One B-rep face of a CAD part: STEP entity #280.
In plain terms, the planar face has unit normal (1, 0, 0).
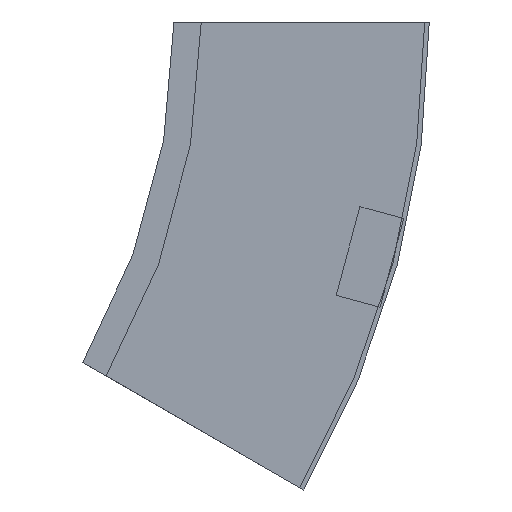
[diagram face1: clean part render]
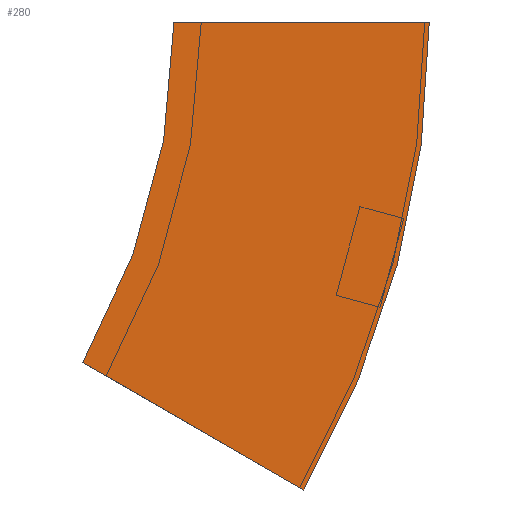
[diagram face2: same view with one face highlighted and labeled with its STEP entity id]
Its self-contained STEP definition (entity closure, numbers rounded to 3 decimals):
#15 = PLANE ( 'NONE',  #28 ) ;
#19 = FACE_OUTER_BOUND ( 'NONE', #211, .T. ) ;
#28 = AXIS2_PLACEMENT_3D ( 'NONE', #197, #443, #109 ) ;
#52 = VERTEX_POINT ( 'NONE', #449 ) ;
#58 = CIRCLE ( 'NONE', #226, 412.5 ) ;
#93 = DIRECTION ( 'NONE',  ( 0., -1., 0. ) ) ;
#94 = CIRCLE ( 'NONE', #444, 300. ) ;
#100 = DIRECTION ( 'NONE',  ( 0., 0.866, 0.5 ) ) ;
#107 = CARTESIAN_POINT ( 'NONE',  ( 0., -57.235, -206.25 ) ) ;
#109 = DIRECTION ( 'NONE',  ( 0., 0., 1. ) ) ;
#117 = VERTEX_POINT ( 'NONE', #232 ) ;
#119 = DIRECTION ( 'NONE',  ( 0., 1., 0. ) ) ;
#120 = VECTOR ( 'NONE', #100, 1000. ) ;
#156 = DIRECTION ( 'NONE',  ( 1., 0., 0. ) ) ;
#163 = VERTEX_POINT ( 'NONE', #438 ) ;
#186 = VERTEX_POINT ( 'NONE', #300 ) ;
#192 = VECTOR ( 'NONE', #119, 1000. ) ;
#197 = CARTESIAN_POINT ( 'NONE',  ( 0., -112.5, 0. ) ) ;
#211 = EDGE_LOOP ( 'NONE', ( #475, #457, #287, #466 ) ) ;
#226 = AXIS2_PLACEMENT_3D ( 'NONE', #346, #524, #93 ) ;
#232 = CARTESIAN_POINT ( 'NONE',  ( 0., -112.5, 0. ) ) ;
#242 = EDGE_CURVE ( 'NONE', #117, #52, #58, .T. ) ;
#280 = ADVANCED_FACE ( 'NONE', ( #19 ), #15, .F. ) ;
#287 = ORIENTED_EDGE ( 'NONE', *, *, #242, .T. ) ;
#300 = CARTESIAN_POINT ( 'NONE',  ( 0., 0., 0. ) ) ;
#335 = EDGE_CURVE ( 'NONE', #52, #163, #364, .T. ) ;
#339 = DIRECTION ( 'NONE',  ( 0., -1., 0. ) ) ;
#346 = CARTESIAN_POINT ( 'NONE',  ( 0., 300., 0. ) ) ;
#364 = LINE ( 'NONE', #107, #120 ) ;
#382 = CARTESIAN_POINT ( 'NONE',  ( 0., 300., 0. ) ) ;
#394 = EDGE_CURVE ( 'NONE', #186, #163, #94, .T. ) ;
#418 = LINE ( 'NONE', #511, #192 ) ;
#438 = CARTESIAN_POINT ( 'NONE',  ( 0., 40.192, -150. ) ) ;
#443 = DIRECTION ( 'NONE',  ( -1., 0., 0. ) ) ;
#444 = AXIS2_PLACEMENT_3D ( 'NONE', #382, #156, #339 ) ;
#449 = CARTESIAN_POINT ( 'NONE',  ( 0., -57.235, -206.25 ) ) ;
#453 = EDGE_CURVE ( 'NONE', #117, #186, #418, .T. ) ;
#457 = ORIENTED_EDGE ( 'NONE', *, *, #453, .F. ) ;
#466 = ORIENTED_EDGE ( 'NONE', *, *, #335, .T. ) ;
#475 = ORIENTED_EDGE ( 'NONE', *, *, #394, .F. ) ;
#511 = CARTESIAN_POINT ( 'NONE',  ( 0., -112.5, 0. ) ) ;
#524 = DIRECTION ( 'NONE',  ( 1., 0., 0. ) ) ;
